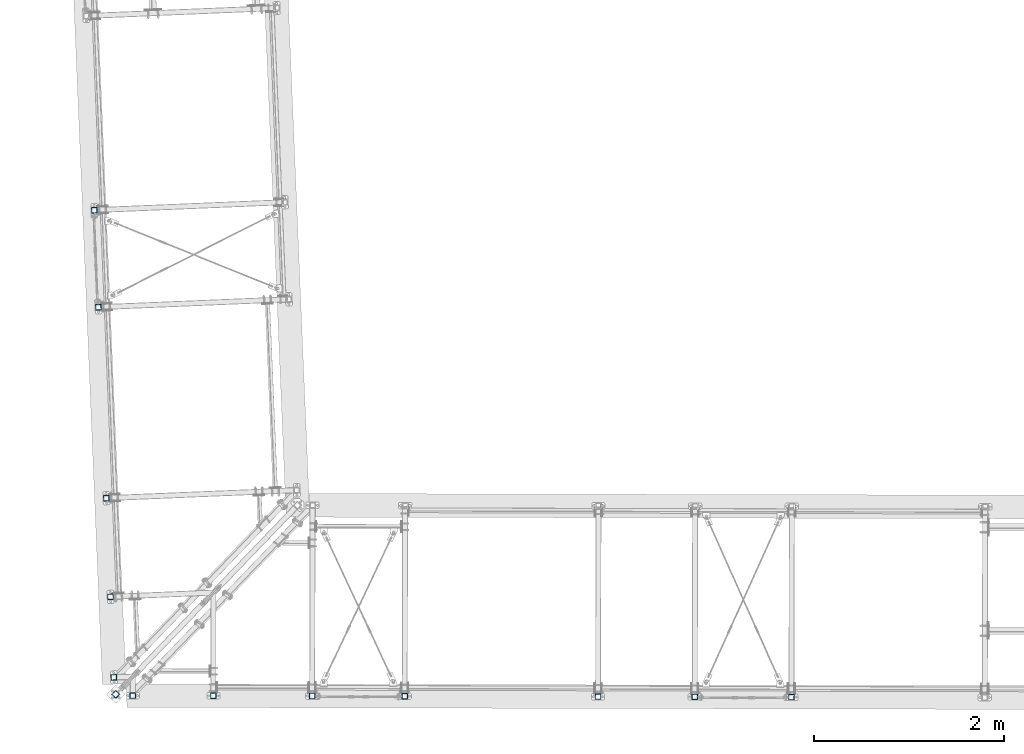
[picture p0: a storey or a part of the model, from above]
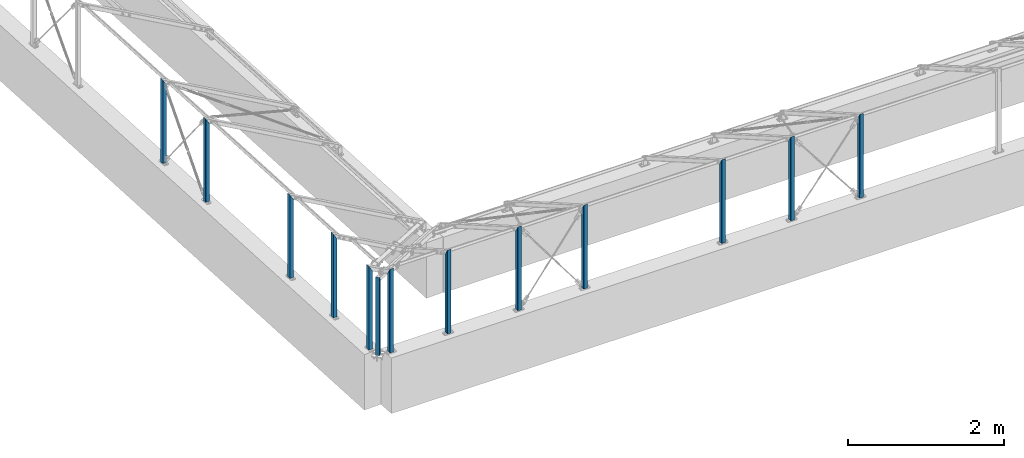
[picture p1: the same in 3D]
Properties of the parts of a building model (IFC2X3)

# File
Description: ViewDefinition[CoordinationView_V2.0]
File name: NCPP_konstrukcja ?wietlika_14-12-2023.ifc
Time: 2023-12-14T12:01:48
Organization: NCPP, ul. Piastowska 14A, 45-081 Opole
Written by: IFC Toolkit 2.0.26.0
Made in: Advance Steel 2024

# IfcBuildingStorey, Default Storey
In: Konstrukcja 1
Elevation: 0 mm

# IfcBeam: TubeBracing (18)
In: Default Storey
Material: S235
Pset_BeamCommon - Slope: 0 deg; IsExternal: no; LoadBearing: no
ProfileProperties - SectionFamily: RHS_Sections_square_c nach DIN
Name | Description = Section | Reference | Span (mm)
2 x TubeBracing | Q40X3 | 1035 | 900.913
4 x TubeBracing | Q40X3 | 1007 | 1960.91
3 x TubeBracing | Q40X3 | 1008 | 941.457
2 x TubeBracing | Q40X3 | 1036 | 897.37
2 x TubeBracing | Q60X3 | 1005 | 982
TubeBracing | Q40X3 | 1050 | 295.893
TubeBracing | Q40X3 | 1011 | 982
TubeBracing | Q40X3 | 1032 | 963.477
TubeBracing | Q40X3 | 1039 | 550.671
TubeBracing | Q40X3 | 1008 | 941.456

# IfcBuildingElementProxy: Turnbuckle (28)
In: Default Storey
Material: Brak

# IfcColumn: - (3)
In: Default Storey
Description: Q60X3; Material: S235
ProfileProperties - SectionFamily: RHS_Sections_square_c nach DIN; Section: Q60X3
Name | Reference | Slope (deg) | IsExternal = LoadBearing
- | 1075 | 0 | no
- | 1077 | 0 | no
-

# IfcColumn: Horizontal_Beam (56)
In: Default Storey
Description: Q60X3; Material: S235
ProfileProperties - SectionFamily: RHS_Sections_square_c nach DIN; Section: Q60X3
Name | Reference | Slope (deg) | IsExternal = LoadBearing
22 x Horizontal_Beam | 1001 | 0 | no
8 x Horizontal_Beam | 1000 | 0 | no
10 x Horizontal_Beam | -10000 | 0 | no
16 x Horizontal_Beam

# IfcMechanicalFastener: - (108)
In: Default Storey
Name | NominalDiameter (mm) | NominalLength (mm)
34 x  | 12 | 100
2 x  | 10 | 90
8 x  | 16 | 50
45 x  | 12 | 90
7 x  | 16 | 95
12 x  | 16 | 100

# IfcMechanicalFastener: Anchor_Bolt (122)
In: Default Storey
NominalDiameter: 10 mm; NominalLength: 90 mm

# IfcMechanicalFastener: Bolt (32)
In: Default Storey
NominalDiameter: 10 mm
Name | NominalLength (mm)
4 x  | 40
28 x  | 45

# IfcMechanicalFastener: Bolt#1 (56)
In: Default Storey
NominalDiameter: 16 mm; NominalLength: 40 mm

# IfcMember: - (15)
In: Default Storey
Description: Q60X3; Material: S235
ProfileProperties - SectionFamily: RHS_Sections_square_c nach DIN; Section: Q60X3
Name
13 x -
- | Pset_MemberCommon - Reference: 1083; Span: 838.157 mm; Slope: 0 deg; IsExternal: no; LoadBearing: no
- | Pset_MemberCommon - Reference: 1079; Span: 1123.84 mm; Slope: 0 deg; IsExternal: no; LoadBearing: no

# IfcMember: Horizontal_Beam (44)
In: Default Storey
Description: Q60X3; Material: S235
ProfileProperties - SectionFamily: RHS_Sections_square_c nach DIN; Section: Q60X3
Name
36 x Horizontal_Beam
Horizontal_Beam | Pset_MemberCommon - Reference: 1074; Span: 1319.15 mm; Slope: 0 deg; IsExternal: no; LoadBearing: no
Horizontal_Beam | Pset_MemberCommon - Reference: 1085; Span: 344.499 mm; Slope: 0 deg; IsExternal: no; LoadBearing: no
Horizontal_Beam | Pset_MemberCommon - Reference: 1128; Span: 831.063 mm; Slope: 0 deg; IsExternal: no; LoadBearing: no
Horizontal_Beam | Pset_MemberCommon - Reference: 1076; Span: 1216.71 mm; Slope: 0 deg; IsExternal: no; LoadBearing: no
Horizontal_Beam | Pset_MemberCommon - Reference: 1081; Span: 1031.39 mm; Slope: 0 deg; IsExternal: no; LoadBearing: no
Horizontal_Beam | Pset_MemberCommon - Reference: 1080; Span: 1101.5 mm; Slope: 0 deg; IsExternal: no; LoadBearing: no
Horizontal_Beam | Pset_MemberCommon - Reference: 1084; Span: 807.059 mm; Slope: 0 deg; IsExternal: no; LoadBearing: no
Horizontal_Beam | Pset_MemberCommon - Reference: 1078; Span: 1160.74 mm; Slope: 0 deg; IsExternal: no; LoadBearing: no

# IfcMember: Tension_Rod#1 (28)
In: Default Storey
Description: RD12; Material: S275J2
ProfileProperties - SectionFamily: Round nach DIN; Section: RD12
Name | Reference | Span (mm) | Slope (deg) | IsExternal = LoadBearing
12 x Tension_Rod#1
2 x Tension_Rod#1 | 1019 | 815.998 | 0 | no
14 x Tension_Rod#1 | 1002 | 599.998 | 0 | no

# IfcMember: Tension_Rod#2 (28)
In: Default Storey
Description: RD12; Material: S275J2
ProfileProperties - SectionFamily: Round nach DIN; Section: RD12
Name | Reference | Span (mm) | Slope (deg) | IsExternal = LoadBearing
2 x Tension_Rod#2 | 1024 | 755.839 | 0 | no
Tension_Rod#2 | 1043 | 758.061 | 0 | no
Tension_Rod#2 | 1042 | 760.329 | 0 | no
2 x Tension_Rod#2
2 x Tension_Rod#2 | 1020 | 791.907 | 0 | no
2 x Tension_Rod#2 | 1004 | 1388.19 | 0 | no
2 x Tension_Rod#2 | 1004 | 1387.69 | 0 | no
2 x Tension_Rod#2 | 1023 | 759 | 0 | no
2 x Tension_Rod#2 | 1021 | 788.529 | 0 | no
2 x Tension_Rod#2 | 1022 | 763.611 | 0 | no
2 x Tension_Rod#2 | 1004 | 1388.28 | 0 | no
2 x Tension_Rod#2 | 1017 | 1374.16 | 0 | no
2 x Tension_Rod#2 | 1018 | 1185.88 | 0 | no
2 x Tension_Rod#2 | 1016 | 1377.71 | 0 | no
2 x Tension_Rod#2 | 1015 | 1973.92 | 0 | no

# IfcMember: TubeBracing (39)
In: Default Storey
Material: S235
Pset_MemberCommon - Slope: 0 deg; IsExternal: no; LoadBearing: no
ProfileProperties - SectionFamily: RHS_Sections_square_c nach DIN
Name | Description = Section | Reference | Span (mm)
2 x TubeBracing | Q40X3 | 1030 | 1936.78
2 x TubeBracing | Q40X3 | 1029 | 1970.91
2 x TubeBracing | Q40X3 | 1034 | 946.457
2 x TubeBracing | Q40X3 | 1028 | 1973.67
3 x TubeBracing | Q40X3 | 1012 | 947.835
2 x TubeBracing | Q40X3 | 1025 | 2086.39
4 x TubeBracing | Q60X3 | 1005 | 982
2 x TubeBracing | Q40X3 | 1027 | 2039.33
2 x TubeBracing | Q40X3 | 1031 | 979.588
2 x TubeBracing | Q40X3 | 1026 | 2056.95
2 x TubeBracing | Q40X3 | 1033 | 958.789
2 x TubeBracing | Q40X3 | 1037 | 882.261
2 x TubeBracing | Q40X3 | 1038 | 645.218
TubeBracing | Q40X3 | 1049 | 298.735
TubeBracing | Q40X3 | 1048 | 315.733
TubeBracing | Q40X3 | 1047 | 327.225
TubeBracing | Q40X3 | 1045 | 606.976
2 x TubeBracing | Q40X3 | 1011 | 982
TubeBracing | Q40X3 | 1039 | 550.851
TubeBracing | Q40X3 | 1032 | 963.525
TubeBracing | Q40X3 | 1044 | 1004.64
TubeBracing | Q40X3 | 1046 | 508.119

# IfcPlate: - (114)
In: Default Storey
Description: -; Material: S235 8 mm
Pset_PlateCommon - IsExternal: no; LoadBearing: no
Name | Reference
79 x - | 1095
7 x - | 1107
12 x - | 1100
8 x - | 1103
6 x - | 1108
- | 1122
- | 1123

# IfcPlate: Baseplate (60)
In: Default Storey
Description: -
Pset_PlateCommon - IsExternal: no; LoadBearing: no
Name | Material | Reference
47 x Baseplate | S235 10 mm | 1096
Baseplate | S235 10 mm | 1120
2 x Baseplate | S235 10 mm | 1115
Baseplate | S235 16 mm | 1121
9 x Baseplate | S235 16 mm | 1102

# IfcPlate: Endplate#1 (16)
In: Default Storey
Description: -; Material: S235 12 mm
Pset_PlateCommon - Reference: 1097; IsExternal: no; LoadBearing: no

# IfcPlate: Endplate#2 (16)
In: Default Storey
Description: -; Material: S235 12 mm
Pset_PlateCommon - Reference: 1097; IsExternal: no; LoadBearing: no

# IfcPlate: Gusset#1 (28)
In: Default Storey
Description: -; Material: S235 8 mm
Pset_PlateCommon - IsExternal: no; LoadBearing: no
Name | Reference
4 x Gusset#1 | 1106
4 x Gusset#1 | 1105
2 x Gusset#1 | 1114
6 x Gusset#1 | 1101
4 x Gusset#1 | 1104
2 x Gusset#1 | 1110
2 x Gusset#1 | 1111
2 x Gusset#1 | 1116
2 x Gusset#1 | 1109

# IfcPlate: Gusset#2 (28)
In: Default Storey
Description: -; Material: S235 8 mm
Pset_PlateCommon - IsExternal: no; LoadBearing: no
Name | Reference
4 x Gusset#2 | 1106
4 x Gusset#2 | 1105
Gusset#2 | 1126
Gusset#2 | 1114
6 x Gusset#2 | 1101
4 x Gusset#2 | 1104
2 x Gusset#2 | 1110
2 x Gusset#2 | 1111
2 x Gusset#2 | 1119
2 x Gusset#2 | 1109

# IfcPlate: Plate (12)
In: Default Storey
Description: -; Material: S235 8 mm
Pset_PlateCommon - IsExternal: no; LoadBearing: no
Name | Reference
3 x Plate | 1112
3 x Plate | 1113
2 x Plate | 1118
2 x Plate | 1117
Plate | 1124
Plate | 1125

# IfcPlate: Tab_Plate#1 (28)
In: Default Storey
Description: -; Material: S235 8 mm
Pset_PlateCommon - IsExternal: no; LoadBearing: no
Name | Reference
14 x Tab_Plate#1 | 1098
14 x Tab_Plate#1 | 1099

# IfcPlate: Tab_Plate#2 (28)
In: Default Storey
Description: -; Material: S235 8 mm
Pset_PlateCommon - IsExternal: no; LoadBearing: no
Name | Reference
14 x Tab_Plate#2 | 1098
14 x Tab_Plate#2 | 1099

# IfcWall: - (8)
In: Default Storey
Description: -
Pset_WallCommon - Reference: Niezdefiniowany; Combustible: no; IsExternal: no; ExtendToStructure: no; LoadBearing: no; Compartmentation: no
Name | Material
6 x - | C25/30 250 mm
- | C25/30 650 mm
- | C25/30 560 mm
